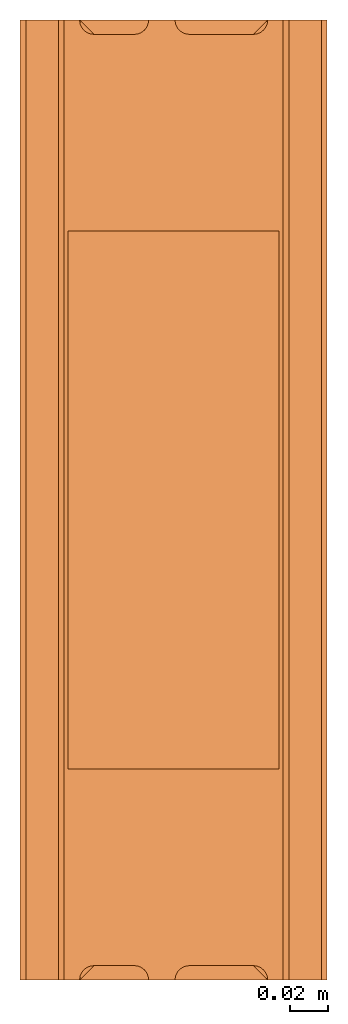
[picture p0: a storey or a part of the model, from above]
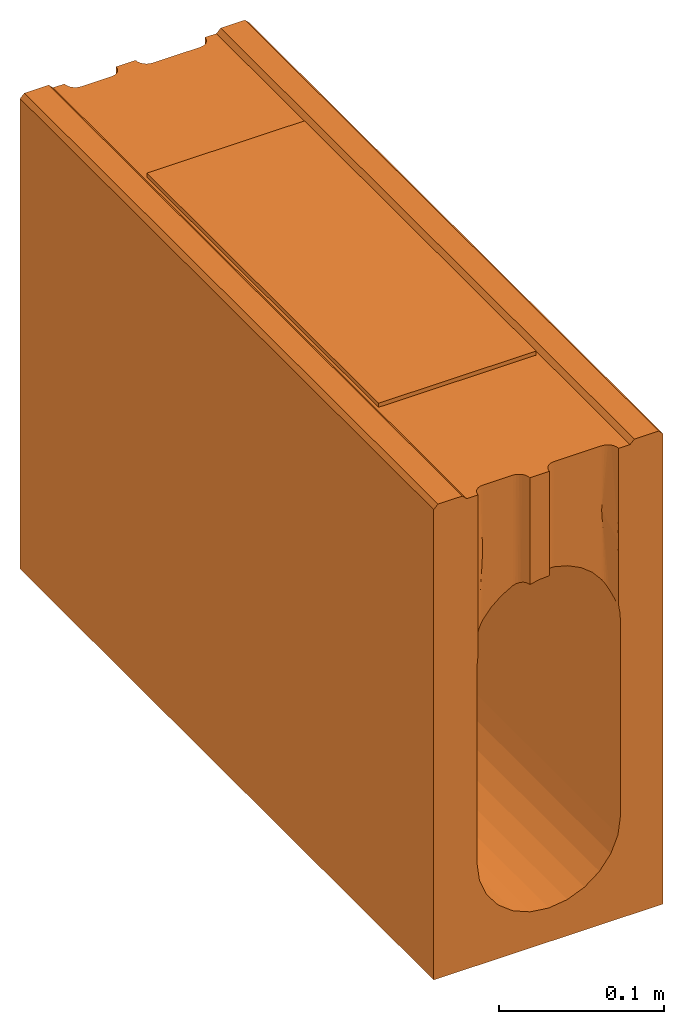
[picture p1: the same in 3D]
Properties of the parts of a building model (IFC2X3)

# File
Description: ViewDefinition [CoordinationView]
File name: 32303 - Junction access unit - 500mm LG.ifc
Time: 2013-09-18T16:28:37
Written by: Autodesk Revit 2013
Made in: 20120221_2030(x64)

# IfcProject, Project Number
LongName: Project Name; Phase: Project Status

# IfcSite, Default
RefLatitude: 42, 21, 30, 344238; RefLongitude: -71, -3, -35, -194702; RefElevation: 0 mm

# IfcBuilding
Pset_BuildingCommon - NumberOfStoreys: 2
Other - Project Issue Date: Issue Date; Project Status: Project Status; Project Address: Enter address here; Project Name: Project Name; Client Name: Owner; Project Number: Project Number

# IfcBuildingStorey (2)
Constraints - Elevation Base: 0
Graphics - Symbol at End 2 Default: yes; Color: 0; Symbol at End 1 Default: no; Symbol: M_Level Head - Circle: M_Level Head - Circle; Line Weight: 1; Line Pattern: Center
Identity Data - Structural: no; Building Story: yes
Dimensions - Computation Height: 0 mm
Name | LongName = Name | Elevation (mm) = Constraints, Elevation (mm)
T.O. Fnd. Wall | T.O. Fnd. Wall | -300
Level 1 | Level 1 | 0

# IfcBuildingElementProxy: 32303 - Junction access unit - 500mm LG, Civil-Drainage-Channel-ACO-KerbDrain-HB480(amar):32303 - Junction access unit - 500mm LG:32303 - Junction access unit - 500mm LG:481515
In: T.O. Fnd. Wall
Material: Acetal Resin, Black
Other - CreatedBy: www.aco.co.uk; Revision: 1
Materials and Finishes - Access Cover/Frame Finish: Water Based Paint Coating; Access Cover/Frame Material: Ductile Iron; End Cap Colour: N/A; Connection Pipe Material: N/A; Connection Pipe Material Colour: N/A; End Cap Material: N/A; Channel Material: Vienite® Synthetic Resin Concrete; Channel Colour: Black; Access Cover/Frame Colour: Black
Phasing - Phase Created: Phase 1
Constraints - Level: Level: Level 1; Moves With Nearby Elements: no
Dimensions - Volume: 16568171 mm3; Void Start I/O: 0 mm; Mitre Long end: 500 mm; Mitre Void End: 6461 mm; Mitre Void Start: 6456 mm; Junction End: 150 mm; Junction Start: 0 mm; Mitre Small End: 487 mm; Void Width: 160 mm; junction void depth: 2000 mm; I/O endcap void depth: 2000 mm; Void End I/O: 150 mm; Void Length: 500 mm; Straight Void Start: 0 mm; Void Depth: -350 mm
Pset_BuildingElementProxyCommon - Reference: 32303 - Junction access unit - 500mm LG
Identity Data - Price: POA - contact ACO; URL: www.aco.co.uk; Installation guidelines: http://www.aco.co.uk/download.php?id=120; Product brochure: http://www.aco.co.uk/download.php?id=120; OmniClass Number: 23.70.50.24; Fax: +44 (0)1462 815895; Cost: 0; Model: ACO KerbDrain HB480; Model Description: Combined kerb and drainage system; OmniClass Title: Rainwater Removal; Product Page URL: http://www.aco.co.uk/product_detail.php?id=3; e-mail Sales: customersupport@aco.co.uk; Assembly Code: D2040; Maintenance guidelines: http://www.aco.co.uk/download.php?id=120; Telephone: +44 (0)1462 816666; Manufacturer: ACO Technologies plc - ACO Water Management Division; e-mail Technical: technical@aco.co.uk; Product Code: 32303; Address: ACO Business Park, Hitchin Road, Shefford, Bedfordshire, United Kingdom SG17 5TE; Type Comments: ACO KerbDrain HB480 half battered junction channel access unit 500mm long; Assembly Description: Rain Water Drainage
Data - Connection Pipe O.D: N/A; Installation - Concrete Grade: Refer to brochure; Load Class: A 15 - D 400; ACO Hydraulic Design Software: http://www.acodesign.co.uk; Invert Depth: 325mm; Product Dimensions: 500mm x 160mm x 350mm (LxWxH); Hydraulic Performance: http://www.aco.co.uk/download.php?id=120; Concrete Surround Volume - Load Class A 15 - D 400 - Concrete Pavement: N/A; Product Weight: 31 Kg; Drainage Slot Intake area: N/A; Channel C.S.A: 0.02m²; Concrete Surround Volume - Load Class A 15 - D 400 - Grass or Asphalt Pavement: N/A; Drainage Slot Width: N/A; Product Standard: BS EN 1433:2002, CE marked, Kitemarked
Construction - Centre Stone: no; Bus stop kerb: no; HB480-500: no; LH inlet/outlet end cap: no; Junction end cap: no; 10-8m external mitre: no; Junction channel: no; perforated centre stone: no; 25-11m internal mitre: no; RH inlet/outlet end cap: no; LH drop kerb: no; RH BS transition kerb: no; 25-11m external mitre: no; Access Unit: no; Junction access unit: yes; Closing end cap: no; 7-6m external mitre: no; cable loop: no; KDHB480 500_blindunit: no; RH drop kerb: no; LH BS transition kerb: no
Green Building Properties - End Cap Recyclable: Fully recyclable; End Cap Recycled Material Content: Between 40% - 90%; Channel Recycled Material Content: 20% minimum; Access Cover/Frame Recycled Material Content: N/A; Channel Recyclable: Fully recyclable; Access Cover/Frame Recyclable: N/A
General - SerialNumber: 0.000000; TagNumber: 0.000000

# IfcOpeningElement: Opening (3)
In: Level 1
Structural - Enable Analytical Model: no; Structural: no
Dimensions - Perimeter: 9790 mm; Area: 5901750 mm2; Thickness: 400 mm; Volume: 2332700000 mm3
Constraints - Level: Level: Level 1; Height Offset From Level: 0 mm; Room Bounding: yes; Related to Mass: no
Phasing - Phase Created: Phase 1
Graphics - Coarse Scale Fill Color: 0
Analytical Properties - Roughness: 1; Thermal mass: 543920; Thermal Resistance (R): 0.477897; Heat Transfer Coefficient (U): 2.0925; Absorptance: 0.1
Construction - Default Thickness: 400 mm; Function: 0
Materials and Finishes - Structural Material: Earth

# IfcSlab: Floor:Generic Floor - 400mm, Floor:Generic Floor - 400mm:136426
In: Level 1
PredefinedType: FLOOR; Material: Earth 400 mm
Structural - Enable Analytical Model: no; Structural: no
Dimensions - Perimeter: 9790 mm; Area: 5901750 mm2; Thickness: 400 mm; Volume: 2332700000 mm3
Constraints - Level: Level: Level 1; Height Offset From Level: 0 mm; Room Bounding: yes; Related to Mass: no
Phasing - Phase Created: Phase 1
Pset_SlabCommon - Reference: Generic Floor - 400mm; IsExternal: no; LoadBearing: yes
Graphics - Coarse Scale Fill Color: 0
Analytical Properties - Roughness: 1; Thermal mass: 543920; Thermal Resistance (R): 0.477897; Heat Transfer Coefficient (U): 2.0925; Absorptance: 0.1
Construction - Default Thickness: 400 mm; Function: 0
Materials and Finishes - Structural Material: Earth
